VERSION 5.7 ;
  NOWIREEXTENSIONATPIN ON ;
  DIVIDERCHAR "/" ;
  BUSBITCHARS "[]" ;
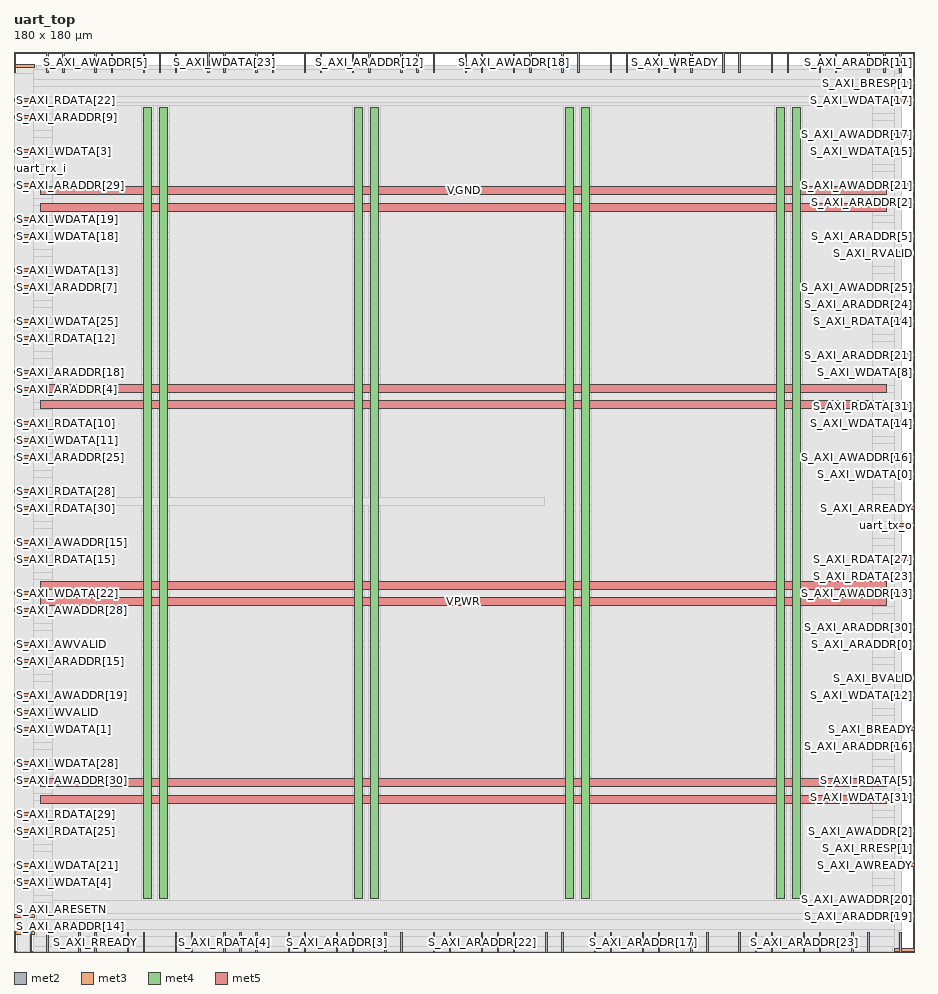
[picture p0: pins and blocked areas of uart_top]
MACRO uart_top
  CLASS BLOCK ;
  FOREIGN uart_top ;
  ORIGIN 0.000 0.000 ;
  SIZE 180.000 BY 180.000 ;
  PIN S_AXI_ACLK
    DIRECTION INPUT ;
    USE SIGNAL ;
    ANTENNAGATEAREA 0.213000 ;
    PORT
      LAYER met2 ;
        RECT 83.810 176.000 84.090 180.000 ;
    END
  END S_AXI_ACLK
  PIN S_AXI_ARADDR[0]
    DIRECTION INPUT ;
    USE SIGNAL ;
    ANTENNAGATEAREA 0.126000 ;
    PORT
      LAYER met3 ;
        RECT 176.000 61.240 180.000 61.840 ;
    END
  END S_AXI_ARADDR[0]
  PIN S_AXI_ARADDR[10]
    DIRECTION INPUT ;
    USE SIGNAL ;
    ANTENNAGATEAREA 0.196500 ;
    PORT
      LAYER met2 ;
        RECT 77.370 176.000 77.650 180.000 ;
    END
  END S_AXI_ARADDR[10]
  PIN S_AXI_ARADDR[11]
    DIRECTION INPUT ;
    USE SIGNAL ;
    ANTENNAGATEAREA 0.196500 ;
    PORT
      LAYER met2 ;
        RECT 170.750 176.000 171.030 180.000 ;
    END
  END S_AXI_ARADDR[11]
  PIN S_AXI_ARADDR[12]
    DIRECTION INPUT ;
    USE SIGNAL ;
    ANTENNAGATEAREA 0.196500 ;
    PORT
      LAYER met2 ;
        RECT 70.930 176.000 71.210 180.000 ;
    END
  END S_AXI_ARADDR[12]
  PIN S_AXI_ARADDR[13]
    DIRECTION INPUT ;
    USE SIGNAL ;
    ANTENNAGATEAREA 0.196500 ;
    PORT
      LAYER met2 ;
        RECT 122.450 176.000 122.730 180.000 ;
    END
  END S_AXI_ARADDR[13]
  PIN S_AXI_ARADDR[14]
    DIRECTION INPUT ;
    USE SIGNAL ;
    ANTENNAGATEAREA 0.126000 ;
    PORT
      LAYER met3 ;
        RECT 0.000 3.440 4.000 4.040 ;
    END
  END S_AXI_ARADDR[14]
  PIN S_AXI_ARADDR[15]
    DIRECTION INPUT ;
    USE SIGNAL ;
    ANTENNAGATEAREA 0.196500 ;
    PORT
      LAYER met3 ;
        RECT 0.000 57.840 4.000 58.440 ;
    END
  END S_AXI_ARADDR[15]
  PIN S_AXI_ARADDR[16]
    DIRECTION INPUT ;
    USE SIGNAL ;
    ANTENNAGATEAREA 0.196500 ;
    PORT
      LAYER met3 ;
        RECT 176.000 40.840 180.000 41.440 ;
    END
  END S_AXI_ARADDR[16]
  PIN S_AXI_ARADDR[17]
    DIRECTION INPUT ;
    USE SIGNAL ;
    ANTENNAGATEAREA 0.196500 ;
    PORT
      LAYER met2 ;
        RECT 125.670 0.000 125.950 4.000 ;
    END
  END S_AXI_ARADDR[17]
  PIN S_AXI_ARADDR[18]
    DIRECTION INPUT ;
    USE SIGNAL ;
    ANTENNAGATEAREA 0.213000 ;
    PORT
      LAYER met3 ;
        RECT 0.000 115.640 4.000 116.240 ;
    END
  END S_AXI_ARADDR[18]
  PIN S_AXI_ARADDR[19]
    DIRECTION INPUT ;
    USE SIGNAL ;
    ANTENNAGATEAREA 0.196500 ;
    PORT
      LAYER met3 ;
        RECT 176.000 6.840 180.000 7.440 ;
    END
  END S_AXI_ARADDR[19]
  PIN S_AXI_ARADDR[1]
    DIRECTION INPUT ;
    USE SIGNAL ;
    ANTENNAGATEAREA 0.196500 ;
    PORT
      LAYER met3 ;
        RECT 0.000 176.840 4.000 177.440 ;
    END
  END S_AXI_ARADDR[1]
  PIN S_AXI_ARADDR[20]
    DIRECTION INPUT ;
    USE SIGNAL ;
    ANTENNAGATEAREA 0.196500 ;
    PORT
      LAYER met2 ;
        RECT 19.410 176.000 19.690 180.000 ;
    END
  END S_AXI_ARADDR[20]
  PIN S_AXI_ARADDR[21]
    DIRECTION INPUT ;
    USE SIGNAL ;
    ANTENNAGATEAREA 0.196500 ;
    PORT
      LAYER met3 ;
        RECT 176.000 119.040 180.000 119.640 ;
    END
  END S_AXI_ARADDR[21]
  PIN S_AXI_ARADDR[22]
    DIRECTION INPUT ;
    USE SIGNAL ;
    ANTENNAGATEAREA 0.196500 ;
    PORT
      LAYER met2 ;
        RECT 93.470 0.000 93.750 4.000 ;
    END
  END S_AXI_ARADDR[22]
  PIN S_AXI_ARADDR[23]
    DIRECTION INPUT ;
    USE SIGNAL ;
    ANTENNAGATEAREA 0.196500 ;
    PORT
      LAYER met2 ;
        RECT 157.870 0.000 158.150 4.000 ;
    END
  END S_AXI_ARADDR[23]
  PIN S_AXI_ARADDR[24]
    DIRECTION INPUT ;
    USE SIGNAL ;
    ANTENNAGATEAREA 0.196500 ;
    PORT
      LAYER met3 ;
        RECT 176.000 129.240 180.000 129.840 ;
    END
  END S_AXI_ARADDR[24]
  PIN S_AXI_ARADDR[25]
    DIRECTION INPUT ;
    USE SIGNAL ;
    ANTENNAGATEAREA 0.196500 ;
    PORT
      LAYER met3 ;
        RECT 0.000 98.640 4.000 99.240 ;
    END
  END S_AXI_ARADDR[25]
  PIN S_AXI_ARADDR[26]
    DIRECTION INPUT ;
    USE SIGNAL ;
    ANTENNAGATEAREA 0.196500 ;
    PORT
      LAYER met2 ;
        RECT 9.750 176.000 10.030 180.000 ;
    END
  END S_AXI_ARADDR[26]
  PIN S_AXI_ARADDR[27]
    DIRECTION INPUT ;
    USE SIGNAL ;
    ANTENNAGATEAREA 0.196500 ;
    PORT
      LAYER met2 ;
        RECT 48.390 176.000 48.670 180.000 ;
    END
  END S_AXI_ARADDR[27]
  PIN S_AXI_ARADDR[28]
    DIRECTION INPUT ;
    USE SIGNAL ;
    ANTENNAGATEAREA 0.196500 ;
    PORT
      LAYER met2 ;
        RECT 25.850 0.000 26.130 4.000 ;
    END
  END S_AXI_ARADDR[28]
  PIN S_AXI_ARADDR[29]
    DIRECTION INPUT ;
    USE SIGNAL ;
    ANTENNAGATEAREA 0.126000 ;
    PORT
      LAYER met3 ;
        RECT 0.000 153.040 4.000 153.640 ;
    END
  END S_AXI_ARADDR[29]
  PIN S_AXI_ARADDR[2]
    DIRECTION INPUT ;
    USE SIGNAL ;
    ANTENNAGATEAREA 0.196500 ;
    PORT
      LAYER met3 ;
        RECT 176.000 149.640 180.000 150.240 ;
    END
  END S_AXI_ARADDR[2]
  PIN S_AXI_ARADDR[30]
    DIRECTION INPUT ;
    USE SIGNAL ;
    ANTENNAGATEAREA 0.196500 ;
    PORT
      LAYER met3 ;
        RECT 176.000 64.640 180.000 65.240 ;
    END
  END S_AXI_ARADDR[30]
  PIN S_AXI_ARADDR[31]
    DIRECTION INPUT ;
    USE SIGNAL ;
    ANTENNAGATEAREA 0.196500 ;
    PORT
      LAYER met2 ;
        RECT 128.890 0.000 129.170 4.000 ;
    END
  END S_AXI_ARADDR[31]
  PIN S_AXI_ARADDR[3]
    DIRECTION INPUT ;
    USE SIGNAL ;
    ANTENNAGATEAREA 0.213000 ;
    PORT
      LAYER met2 ;
        RECT 64.490 0.000 64.770 4.000 ;
    END
  END S_AXI_ARADDR[3]
  PIN S_AXI_ARADDR[4]
    DIRECTION INPUT ;
    USE SIGNAL ;
    ANTENNAGATEAREA 0.196500 ;
    PORT
      LAYER met3 ;
        RECT 0.000 112.240 4.000 112.840 ;
    END
  END S_AXI_ARADDR[4]
  PIN S_AXI_ARADDR[5]
    DIRECTION INPUT ;
    USE SIGNAL ;
    ANTENNAGATEAREA 0.196500 ;
    PORT
      LAYER met3 ;
        RECT 176.000 142.840 180.000 143.440 ;
    END
  END S_AXI_ARADDR[5]
  PIN S_AXI_ARADDR[6]
    DIRECTION INPUT ;
    USE SIGNAL ;
    ANTENNAGATEAREA 0.196500 ;
    PORT
      LAYER met2 ;
        RECT 112.790 176.000 113.070 180.000 ;
    END
  END S_AXI_ARADDR[6]
  PIN S_AXI_ARADDR[7]
    DIRECTION INPUT ;
    USE SIGNAL ;
    ANTENNAGATEAREA 0.196500 ;
    PORT
      LAYER met3 ;
        RECT 0.000 132.640 4.000 133.240 ;
    END
  END S_AXI_ARADDR[7]
  PIN S_AXI_ARADDR[8]
    DIRECTION INPUT ;
    USE SIGNAL ;
    ANTENNAGATEAREA 0.126000 ;
    PORT
      LAYER met2 ;
        RECT 45.170 0.000 45.450 4.000 ;
    END
  END S_AXI_ARADDR[8]
  PIN S_AXI_ARADDR[9]
    DIRECTION INPUT ;
    USE SIGNAL ;
    ANTENNAGATEAREA 0.196500 ;
    PORT
      LAYER met3 ;
        RECT 0.000 166.640 4.000 167.240 ;
    END
  END S_AXI_ARADDR[9]
  PIN S_AXI_ARESETN
    DIRECTION INPUT ;
    USE SIGNAL ;
    ANTENNAGATEAREA 0.213000 ;
    PORT
      LAYER met3 ;
        RECT 0.000 6.840 4.000 7.440 ;
    END
  END S_AXI_ARESETN
  PIN S_AXI_ARREADY
    DIRECTION OUTPUT TRISTATE ;
    USE SIGNAL ;
    ANTENNADIFFAREA 0.795200 ;
    PORT
      LAYER met3 ;
        RECT 176.000 88.440 180.000 89.040 ;
    END
  END S_AXI_ARREADY
  PIN S_AXI_ARVALID
    DIRECTION INPUT ;
    USE SIGNAL ;
    ANTENNAGATEAREA 0.196500 ;
    PORT
      LAYER met2 ;
        RECT 177.190 176.000 177.470 180.000 ;
    END
  END S_AXI_ARVALID
  PIN S_AXI_AWADDR[0]
    DIRECTION INPUT ;
    USE SIGNAL ;
    ANTENNAGATEAREA 0.196500 ;
    PORT
      LAYER met2 ;
        RECT 58.050 176.000 58.330 180.000 ;
    END
  END S_AXI_AWADDR[0]
  PIN S_AXI_AWADDR[10]
    DIRECTION INPUT ;
    USE SIGNAL ;
    ANTENNAGATEAREA 0.196500 ;
    PORT
      LAYER met2 ;
        RECT 12.970 0.000 13.250 4.000 ;
    END
  END S_AXI_AWADDR[10]
  PIN S_AXI_AWADDR[11]
    DIRECTION INPUT ;
    USE SIGNAL ;
    ANTENNAGATEAREA 0.196500 ;
    PORT
      LAYER met2 ;
        RECT 54.830 0.000 55.110 4.000 ;
    END
  END S_AXI_AWADDR[11]
  PIN S_AXI_AWADDR[12]
    DIRECTION INPUT ;
    USE SIGNAL ;
    ANTENNAGATEAREA 0.196500 ;
    PORT
      LAYER met2 ;
        RECT 167.530 0.000 167.810 4.000 ;
    END
  END S_AXI_AWADDR[12]
  PIN S_AXI_AWADDR[13]
    DIRECTION INPUT ;
    USE SIGNAL ;
    ANTENNAGATEAREA 0.196500 ;
    PORT
      LAYER met3 ;
        RECT 176.000 71.440 180.000 72.040 ;
    END
  END S_AXI_AWADDR[13]
  PIN S_AXI_AWADDR[14]
    DIRECTION INPUT ;
    USE SIGNAL ;
    ANTENNAGATEAREA 0.196500 ;
    PORT
      LAYER met2 ;
        RECT 116.010 0.000 116.290 4.000 ;
    END
  END S_AXI_AWADDR[14]
  PIN S_AXI_AWADDR[15]
    DIRECTION INPUT ;
    USE SIGNAL ;
    ANTENNAGATEAREA 0.196500 ;
    PORT
      LAYER met3 ;
        RECT 0.000 81.640 4.000 82.240 ;
    END
  END S_AXI_AWADDR[15]
  PIN S_AXI_AWADDR[16]
    DIRECTION INPUT ;
    USE SIGNAL ;
    ANTENNAGATEAREA 0.196500 ;
    PORT
      LAYER met3 ;
        RECT 176.000 98.640 180.000 99.240 ;
    END
  END S_AXI_AWADDR[16]
  PIN S_AXI_AWADDR[17]
    DIRECTION INPUT ;
    USE SIGNAL ;
    ANTENNAGATEAREA 0.196500 ;
    PORT
      LAYER met3 ;
        RECT 176.000 163.240 180.000 163.840 ;
    END
  END S_AXI_AWADDR[17]
  PIN S_AXI_AWADDR[18]
    DIRECTION INPUT ;
    USE SIGNAL ;
    ANTENNAGATEAREA 0.196500 ;
    PORT
      LAYER met2 ;
        RECT 99.910 176.000 100.190 180.000 ;
    END
  END S_AXI_AWADDR[18]
  PIN S_AXI_AWADDR[19]
    DIRECTION INPUT ;
    USE SIGNAL ;
    ANTENNAGATEAREA 0.126000 ;
    PORT
      LAYER met3 ;
        RECT 0.000 51.040 4.000 51.640 ;
    END
  END S_AXI_AWADDR[19]
  PIN S_AXI_AWADDR[1]
    DIRECTION INPUT ;
    USE SIGNAL ;
    ANTENNAGATEAREA 0.196500 ;
    PORT
      LAYER met2 ;
        RECT 80.590 176.000 80.870 180.000 ;
    END
  END S_AXI_AWADDR[1]
  PIN S_AXI_AWADDR[20]
    DIRECTION INPUT ;
    USE SIGNAL ;
    ANTENNAGATEAREA 0.196500 ;
    PORT
      LAYER met3 ;
        RECT 176.000 10.240 180.000 10.840 ;
    END
  END S_AXI_AWADDR[20]
  PIN S_AXI_AWADDR[21]
    DIRECTION INPUT ;
    USE SIGNAL ;
    ANTENNAGATEAREA 0.196500 ;
    PORT
      LAYER met3 ;
        RECT 176.000 153.040 180.000 153.640 ;
    END
  END S_AXI_AWADDR[21]
  PIN S_AXI_AWADDR[22]
    DIRECTION INPUT ;
    USE SIGNAL ;
    ANTENNAGATEAREA 0.196500 ;
    PORT
      LAYER met2 ;
        RECT 173.970 176.000 174.250 180.000 ;
    END
  END S_AXI_AWADDR[22]
  PIN S_AXI_AWADDR[23]
    DIRECTION INPUT ;
    USE SIGNAL ;
    ANTENNAGATEAREA 0.196500 ;
    PORT
      LAYER met2 ;
        RECT 61.270 176.000 61.550 180.000 ;
    END
  END S_AXI_AWADDR[23]
  PIN S_AXI_AWADDR[24]
    DIRECTION INPUT ;
    USE SIGNAL ;
    ANTENNAGATEAREA 0.196500 ;
    PORT
      LAYER met2 ;
        RECT 144.990 176.000 145.270 180.000 ;
    END
  END S_AXI_AWADDR[24]
  PIN S_AXI_AWADDR[25]
    DIRECTION INPUT ;
    USE SIGNAL ;
    ANTENNAGATEAREA 0.196500 ;
    PORT
      LAYER met3 ;
        RECT 176.000 132.640 180.000 133.240 ;
    END
  END S_AXI_AWADDR[25]
  PIN S_AXI_AWADDR[26]
    DIRECTION INPUT ;
    USE SIGNAL ;
    ANTENNAGATEAREA 0.196500 ;
    PORT
      LAYER met2 ;
        RECT 119.230 176.000 119.510 180.000 ;
    END
  END S_AXI_AWADDR[26]
  PIN S_AXI_AWADDR[27]
    DIRECTION INPUT ;
    USE SIGNAL ;
    ANTENNAGATEAREA 0.196500 ;
    PORT
      LAYER met2 ;
        RECT 135.330 0.000 135.610 4.000 ;
    END
  END S_AXI_AWADDR[27]
  PIN S_AXI_AWADDR[28]
    DIRECTION INPUT ;
    USE SIGNAL ;
    ANTENNAGATEAREA 0.196500 ;
    PORT
      LAYER met3 ;
        RECT 0.000 68.040 4.000 68.640 ;
    END
  END S_AXI_AWADDR[28]
  PIN S_AXI_AWADDR[29]
    DIRECTION INPUT ;
    USE SIGNAL ;
    ANTENNAGATEAREA 0.196500 ;
    PORT
      LAYER met2 ;
        RECT 83.810 0.000 84.090 4.000 ;
    END
  END S_AXI_AWADDR[29]
  PIN S_AXI_AWADDR[2]
    DIRECTION INPUT ;
    USE SIGNAL ;
    ANTENNAGATEAREA 0.213000 ;
    PORT
      LAYER met3 ;
        RECT 176.000 23.840 180.000 24.440 ;
    END
  END S_AXI_AWADDR[2]
  PIN S_AXI_AWADDR[30]
    DIRECTION INPUT ;
    USE SIGNAL ;
    ANTENNAGATEAREA 0.196500 ;
    PORT
      LAYER met3 ;
        RECT 0.000 34.040 4.000 34.640 ;
    END
  END S_AXI_AWADDR[30]
  PIN S_AXI_AWADDR[31]
    DIRECTION INPUT ;
    USE SIGNAL ;
    ANTENNAGATEAREA 0.126000 ;
    PORT
      LAYER met2 ;
        RECT 151.430 176.000 151.710 180.000 ;
    END
  END S_AXI_AWADDR[31]
  PIN S_AXI_AWADDR[3]
    DIRECTION INPUT ;
    USE SIGNAL ;
    ANTENNAGATEAREA 0.213000 ;
    PORT
      LAYER met2 ;
        RECT 74.150 0.000 74.430 4.000 ;
    END
  END S_AXI_AWADDR[3]
  PIN S_AXI_AWADDR[4]
    DIRECTION INPUT ;
    USE SIGNAL ;
    ANTENNAGATEAREA 0.126000 ;
    PORT
      LAYER met2 ;
        RECT 109.570 0.000 109.850 4.000 ;
    END
  END S_AXI_AWADDR[4]
  PIN S_AXI_AWADDR[5]
    DIRECTION INPUT ;
    USE SIGNAL ;
    ANTENNAGATEAREA 0.196500 ;
    PORT
      LAYER met2 ;
        RECT 16.190 176.000 16.470 180.000 ;
    END
  END S_AXI_AWADDR[5]
  PIN S_AXI_AWADDR[6]
    DIRECTION INPUT ;
    USE SIGNAL ;
    ANTENNAGATEAREA 0.126000 ;
    PORT
      LAYER met2 ;
        RECT 48.390 0.000 48.670 4.000 ;
    END
  END S_AXI_AWADDR[6]
  PIN S_AXI_AWADDR[7]
    DIRECTION INPUT ;
    USE SIGNAL ;
    ANTENNAGATEAREA 0.196500 ;
    PORT
      LAYER met2 ;
        RECT 6.530 176.000 6.810 180.000 ;
    END
  END S_AXI_AWADDR[7]
  PIN S_AXI_AWADDR[8]
    DIRECTION INPUT ;
    USE SIGNAL ;
    ANTENNAGATEAREA 0.196500 ;
    PORT
      LAYER met2 ;
        RECT 90.250 176.000 90.530 180.000 ;
    END
  END S_AXI_AWADDR[8]
  PIN S_AXI_AWADDR[9]
    DIRECTION INPUT ;
    USE SIGNAL ;
    ANTENNAGATEAREA 0.196500 ;
    PORT
      LAYER met2 ;
        RECT 151.430 0.000 151.710 4.000 ;
    END
  END S_AXI_AWADDR[9]
  PIN S_AXI_AWREADY
    DIRECTION OUTPUT TRISTATE ;
    USE SIGNAL ;
    ANTENNADIFFAREA 0.795200 ;
    PORT
      LAYER met3 ;
        RECT 176.000 17.040 180.000 17.640 ;
    END
  END S_AXI_AWREADY
  PIN S_AXI_AWVALID
    DIRECTION INPUT ;
    USE SIGNAL ;
    ANTENNAGATEAREA 0.196500 ;
    PORT
      LAYER met3 ;
        RECT 0.000 61.240 4.000 61.840 ;
    END
  END S_AXI_AWVALID
  PIN S_AXI_BREADY
    DIRECTION INPUT ;
    USE SIGNAL ;
    ANTENNAGATEAREA 0.196500 ;
    PORT
      LAYER met3 ;
        RECT 176.000 44.240 180.000 44.840 ;
    END
  END S_AXI_BREADY
  PIN S_AXI_BRESP[0]
    DIRECTION OUTPUT TRISTATE ;
    USE SIGNAL ;
    PORT
      LAYER met2 ;
        RECT 144.990 0.000 145.270 4.000 ;
    END
  END S_AXI_BRESP[0]
  PIN S_AXI_BRESP[1]
    DIRECTION OUTPUT TRISTATE ;
    USE SIGNAL ;
    PORT
      LAYER met3 ;
        RECT 176.000 173.440 180.000 174.040 ;
    END
  END S_AXI_BRESP[1]
  PIN S_AXI_BVALID
    DIRECTION OUTPUT TRISTATE ;
    USE SIGNAL ;
    ANTENNADIFFAREA 0.795200 ;
    PORT
      LAYER met3 ;
        RECT 176.000 54.440 180.000 55.040 ;
    END
  END S_AXI_BVALID
  PIN S_AXI_RDATA[0]
    DIRECTION OUTPUT TRISTATE ;
    USE SIGNAL ;
    ANTENNADIFFAREA 0.795200 ;
    PORT
      LAYER met2 ;
        RECT 77.370 0.000 77.650 4.000 ;
    END
  END S_AXI_RDATA[0]
  PIN S_AXI_RDATA[10]
    DIRECTION OUTPUT TRISTATE ;
    USE SIGNAL ;
    ANTENNADIFFAREA 0.795200 ;
    PORT
      LAYER met3 ;
        RECT 0.000 105.440 4.000 106.040 ;
    END
  END S_AXI_RDATA[10]
  PIN S_AXI_RDATA[11]
    DIRECTION OUTPUT TRISTATE ;
    USE SIGNAL ;
    ANTENNADIFFAREA 0.795200 ;
    PORT
      LAYER met2 ;
        RECT 135.330 176.000 135.610 180.000 ;
    END
  END S_AXI_RDATA[11]
  PIN S_AXI_RDATA[12]
    DIRECTION OUTPUT TRISTATE ;
    USE SIGNAL ;
    ANTENNADIFFAREA 0.795200 ;
    PORT
      LAYER met3 ;
        RECT 0.000 122.440 4.000 123.040 ;
    END
  END S_AXI_RDATA[12]
  PIN S_AXI_RDATA[13]
    DIRECTION OUTPUT TRISTATE ;
    USE SIGNAL ;
    ANTENNADIFFAREA 0.445500 ;
    PORT
      LAYER met2 ;
        RECT 38.730 176.000 39.010 180.000 ;
    END
  END S_AXI_RDATA[13]
  PIN S_AXI_RDATA[14]
    DIRECTION OUTPUT TRISTATE ;
    USE SIGNAL ;
    ANTENNADIFFAREA 0.795200 ;
    PORT
      LAYER met3 ;
        RECT 176.000 125.840 180.000 126.440 ;
    END
  END S_AXI_RDATA[14]
  PIN S_AXI_RDATA[15]
    DIRECTION OUTPUT TRISTATE ;
    USE SIGNAL ;
    ANTENNADIFFAREA 0.795200 ;
    PORT
      LAYER met3 ;
        RECT 0.000 78.240 4.000 78.840 ;
    END
  END S_AXI_RDATA[15]
  PIN S_AXI_RDATA[16]
    DIRECTION OUTPUT TRISTATE ;
    USE SIGNAL ;
    ANTENNADIFFAREA 0.445500 ;
    PORT
      LAYER met2 ;
        RECT 141.770 176.000 142.050 180.000 ;
    END
  END S_AXI_RDATA[16]
  PIN S_AXI_RDATA[17]
    DIRECTION OUTPUT TRISTATE ;
    USE SIGNAL ;
    ANTENNADIFFAREA 0.795200 ;
    PORT
      LAYER met2 ;
        RECT 109.570 176.000 109.850 180.000 ;
    END
  END S_AXI_RDATA[17]
  PIN S_AXI_RDATA[18]
    DIRECTION OUTPUT TRISTATE ;
    USE SIGNAL ;
    ANTENNADIFFAREA 0.445500 ;
    PORT
      LAYER met2 ;
        RECT 161.090 176.000 161.370 180.000 ;
    END
  END S_AXI_RDATA[18]
  PIN S_AXI_RDATA[19]
    DIRECTION OUTPUT TRISTATE ;
    USE SIGNAL ;
    ANTENNADIFFAREA 0.795200 ;
    PORT
      LAYER met2 ;
        RECT 3.310 0.000 3.590 4.000 ;
    END
  END S_AXI_RDATA[19]
  PIN S_AXI_RDATA[1]
    DIRECTION OUTPUT TRISTATE ;
    USE SIGNAL ;
    ANTENNADIFFAREA 0.795200 ;
    PORT
      LAYER met2 ;
        RECT 22.630 0.000 22.910 4.000 ;
    END
  END S_AXI_RDATA[1]
  PIN S_AXI_RDATA[20]
    DIRECTION OUTPUT TRISTATE ;
    USE SIGNAL ;
    ANTENNADIFFAREA 0.795200 ;
    PORT
      LAYER met3 ;
        RECT 176.000 0.040 180.000 0.640 ;
    END
  END S_AXI_RDATA[20]
  PIN S_AXI_RDATA[21]
    DIRECTION OUTPUT TRISTATE ;
    USE SIGNAL ;
    ANTENNADIFFAREA 0.795200 ;
    PORT
      LAYER met2 ;
        RECT 29.070 176.000 29.350 180.000 ;
    END
  END S_AXI_RDATA[21]
  PIN S_AXI_RDATA[22]
    DIRECTION OUTPUT TRISTATE ;
    USE SIGNAL ;
    ANTENNADIFFAREA 0.795200 ;
    PORT
      LAYER met3 ;
        RECT 0.000 170.040 4.000 170.640 ;
    END
  END S_AXI_RDATA[22]
  PIN S_AXI_RDATA[23]
    DIRECTION OUTPUT TRISTATE ;
    USE SIGNAL ;
    ANTENNADIFFAREA 0.795200 ;
    PORT
      LAYER met3 ;
        RECT 176.000 74.840 180.000 75.440 ;
    END
  END S_AXI_RDATA[23]
  PIN S_AXI_RDATA[24]
    DIRECTION OUTPUT TRISTATE ;
    USE SIGNAL ;
    ANTENNADIFFAREA 0.795200 ;
    PORT
      LAYER met2 ;
        RECT 67.710 176.000 67.990 180.000 ;
    END
  END S_AXI_RDATA[24]
  PIN S_AXI_RDATA[25]
    DIRECTION OUTPUT TRISTATE ;
    USE SIGNAL ;
    ANTENNADIFFAREA 0.795200 ;
    PORT
      LAYER met3 ;
        RECT 0.000 23.840 4.000 24.440 ;
    END
  END S_AXI_RDATA[25]
  PIN S_AXI_RDATA[26]
    DIRECTION OUTPUT TRISTATE ;
    USE SIGNAL ;
    ANTENNADIFFAREA 0.795200 ;
    PORT
      LAYER met2 ;
        RECT 25.850 176.000 26.130 180.000 ;
    END
  END S_AXI_RDATA[26]
  PIN S_AXI_RDATA[27]
    DIRECTION OUTPUT TRISTATE ;
    USE SIGNAL ;
    ANTENNADIFFAREA 0.795200 ;
    PORT
      LAYER met3 ;
        RECT 176.000 78.240 180.000 78.840 ;
    END
  END S_AXI_RDATA[27]
  PIN S_AXI_RDATA[28]
    DIRECTION OUTPUT TRISTATE ;
    USE SIGNAL ;
    ANTENNADIFFAREA 0.795200 ;
    PORT
      LAYER met3 ;
        RECT 0.000 91.840 4.000 92.440 ;
    END
  END S_AXI_RDATA[28]
  PIN S_AXI_RDATA[29]
    DIRECTION OUTPUT TRISTATE ;
    USE SIGNAL ;
    ANTENNADIFFAREA 0.795200 ;
    PORT
      LAYER met3 ;
        RECT 0.000 27.240 4.000 27.840 ;
    END
  END S_AXI_RDATA[29]
  PIN S_AXI_RDATA[2]
    DIRECTION OUTPUT TRISTATE ;
    USE SIGNAL ;
    ANTENNADIFFAREA 0.795200 ;
    PORT
      LAYER met2 ;
        RECT 170.750 0.000 171.030 4.000 ;
    END
  END S_AXI_RDATA[2]
  PIN S_AXI_RDATA[30]
    DIRECTION OUTPUT TRISTATE ;
    USE SIGNAL ;
    ANTENNADIFFAREA 0.795200 ;
    PORT
      LAYER met3 ;
        RECT 0.000 88.440 4.000 89.040 ;
    END
  END S_AXI_RDATA[30]
  PIN S_AXI_RDATA[31]
    DIRECTION OUTPUT TRISTATE ;
    USE SIGNAL ;
    ANTENNADIFFAREA 0.795200 ;
    PORT
      LAYER met3 ;
        RECT 176.000 108.840 180.000 109.440 ;
    END
  END S_AXI_RDATA[31]
  PIN S_AXI_RDATA[3]
    DIRECTION OUTPUT TRISTATE ;
    USE SIGNAL ;
    ANTENNADIFFAREA 0.795200 ;
    PORT
      LAYER met2 ;
        RECT 164.310 176.000 164.590 180.000 ;
    END
  END S_AXI_RDATA[3]
  PIN S_AXI_RDATA[4]
    DIRECTION OUTPUT TRISTATE ;
    USE SIGNAL ;
    ANTENNADIFFAREA 0.795200 ;
    PORT
      LAYER met2 ;
        RECT 41.950 0.000 42.230 4.000 ;
    END
  END S_AXI_RDATA[4]
  PIN S_AXI_RDATA[5]
    DIRECTION OUTPUT TRISTATE ;
    USE SIGNAL ;
    ANTENNADIFFAREA 0.795200 ;
    PORT
      LAYER met3 ;
        RECT 176.000 34.040 180.000 34.640 ;
    END
  END S_AXI_RDATA[5]
  PIN S_AXI_RDATA[6]
    DIRECTION OUTPUT TRISTATE ;
    USE SIGNAL ;
    ANTENNADIFFAREA 0.795200 ;
    PORT
      LAYER met2 ;
        RECT 106.350 0.000 106.630 4.000 ;
    END
  END S_AXI_RDATA[6]
  PIN S_AXI_RDATA[7]
    DIRECTION OUTPUT TRISTATE ;
    USE SIGNAL ;
    ANTENNADIFFAREA 0.795200 ;
    PORT
      LAYER met2 ;
        RECT 177.190 0.000 177.470 4.000 ;
    END
  END S_AXI_RDATA[7]
  PIN S_AXI_RDATA[8]
    DIRECTION OUTPUT TRISTATE ;
    USE SIGNAL ;
    ANTENNADIFFAREA 0.445500 ;
    PORT
      LAYER met2 ;
        RECT 51.610 176.000 51.890 180.000 ;
    END
  END S_AXI_RDATA[8]
  PIN S_AXI_RDATA[9]
    DIRECTION OUTPUT TRISTATE ;
    USE SIGNAL ;
    ANTENNADIFFAREA 0.795200 ;
    PORT
      LAYER met2 ;
        RECT 138.550 0.000 138.830 4.000 ;
    END
  END S_AXI_RDATA[9]
  PIN S_AXI_RREADY
    DIRECTION INPUT ;
    USE SIGNAL ;
    ANTENNAGATEAREA 0.213000 ;
    PORT
      LAYER met2 ;
        RECT 16.190 0.000 16.470 4.000 ;
    END
  END S_AXI_RREADY
  PIN S_AXI_RRESP[0]
    DIRECTION OUTPUT TRISTATE ;
    USE SIGNAL ;
    PORT
      LAYER met2 ;
        RECT 67.710 0.000 67.990 4.000 ;
    END
  END S_AXI_RRESP[0]
  PIN S_AXI_RRESP[1]
    DIRECTION OUTPUT TRISTATE ;
    USE SIGNAL ;
    PORT
      LAYER met3 ;
        RECT 176.000 20.440 180.000 21.040 ;
    END
  END S_AXI_RRESP[1]
  PIN S_AXI_RVALID
    DIRECTION OUTPUT TRISTATE ;
    USE SIGNAL ;
    ANTENNADIFFAREA 0.795200 ;
    PORT
      LAYER met3 ;
        RECT 176.000 139.440 180.000 140.040 ;
    END
  END S_AXI_RVALID
  PIN S_AXI_WDATA[0]
    DIRECTION INPUT ;
    USE SIGNAL ;
    ANTENNAGATEAREA 0.213000 ;
    PORT
      LAYER met3 ;
        RECT 176.000 95.240 180.000 95.840 ;
    END
  END S_AXI_WDATA[0]
  PIN S_AXI_WDATA[10]
    DIRECTION INPUT ;
    USE SIGNAL ;
    ANTENNAGATEAREA 0.213000 ;
    PORT
      LAYER met2 ;
        RECT 148.210 0.000 148.490 4.000 ;
    END
  END S_AXI_WDATA[10]
  PIN S_AXI_WDATA[11]
    DIRECTION INPUT ;
    USE SIGNAL ;
    ANTENNAGATEAREA 0.213000 ;
    PORT
      LAYER met3 ;
        RECT 0.000 102.040 4.000 102.640 ;
    END
  END S_AXI_WDATA[11]
  PIN S_AXI_WDATA[12]
    DIRECTION INPUT ;
    USE SIGNAL ;
    ANTENNAGATEAREA 0.213000 ;
    PORT
      LAYER met3 ;
        RECT 176.000 51.040 180.000 51.640 ;
    END
  END S_AXI_WDATA[12]
  PIN S_AXI_WDATA[13]
    DIRECTION INPUT ;
    USE SIGNAL ;
    ANTENNAGATEAREA 0.213000 ;
    PORT
      LAYER met3 ;
        RECT 0.000 136.040 4.000 136.640 ;
    END
  END S_AXI_WDATA[13]
  PIN S_AXI_WDATA[14]
    DIRECTION INPUT ;
    USE SIGNAL ;
    ANTENNAGATEAREA 0.213000 ;
    PORT
      LAYER met3 ;
        RECT 176.000 105.440 180.000 106.040 ;
    END
  END S_AXI_WDATA[14]
  PIN S_AXI_WDATA[15]
    DIRECTION INPUT ;
    USE SIGNAL ;
    ANTENNAGATEAREA 0.213000 ;
    PORT
      LAYER met3 ;
        RECT 176.000 159.840 180.000 160.440 ;
    END
  END S_AXI_WDATA[15]
  PIN S_AXI_WDATA[16]
    DIRECTION INPUT ;
    USE SIGNAL ;
    ANTENNAGATEAREA 0.159000 ;
    PORT
      LAYER met2 ;
        RECT 161.090 0.000 161.370 4.000 ;
    END
  END S_AXI_WDATA[16]
  PIN S_AXI_WDATA[17]
    DIRECTION INPUT ;
    USE SIGNAL ;
    ANTENNAGATEAREA 0.159000 ;
    PORT
      LAYER met3 ;
        RECT 176.000 170.040 180.000 170.640 ;
    END
  END S_AXI_WDATA[17]
  PIN S_AXI_WDATA[18]
    DIRECTION INPUT ;
    USE SIGNAL ;
    ANTENNAGATEAREA 0.196500 ;
    PORT
      LAYER met3 ;
        RECT 0.000 142.840 4.000 143.440 ;
    END
  END S_AXI_WDATA[18]
  PIN S_AXI_WDATA[19]
    DIRECTION INPUT ;
    USE SIGNAL ;
    ANTENNAGATEAREA 0.196500 ;
    PORT
      LAYER met3 ;
        RECT 0.000 146.240 4.000 146.840 ;
    END
  END S_AXI_WDATA[19]
  PIN S_AXI_WDATA[1]
    DIRECTION INPUT ;
    USE SIGNAL ;
    ANTENNAGATEAREA 0.213000 ;
    PORT
      LAYER met3 ;
        RECT 0.000 44.240 4.000 44.840 ;
    END
  END S_AXI_WDATA[1]
  PIN S_AXI_WDATA[20]
    DIRECTION INPUT ;
    USE SIGNAL ;
    ANTENNAGATEAREA 0.126000 ;
    PORT
      LAYER met2 ;
        RECT 0.090 0.000 0.370 4.000 ;
    END
  END S_AXI_WDATA[20]
  PIN S_AXI_WDATA[21]
    DIRECTION INPUT ;
    USE SIGNAL ;
    ANTENNAGATEAREA 0.126000 ;
    PORT
      LAYER met3 ;
        RECT 0.000 17.040 4.000 17.640 ;
    END
  END S_AXI_WDATA[21]
  PIN S_AXI_WDATA[22]
    DIRECTION INPUT ;
    USE SIGNAL ;
    ANTENNAGATEAREA 0.196500 ;
    PORT
      LAYER met3 ;
        RECT 0.000 71.440 4.000 72.040 ;
    END
  END S_AXI_WDATA[22]
  PIN S_AXI_WDATA[23]
    DIRECTION INPUT ;
    USE SIGNAL ;
    ANTENNAGATEAREA 0.126000 ;
    PORT
      LAYER met2 ;
        RECT 41.950 176.000 42.230 180.000 ;
    END
  END S_AXI_WDATA[23]
  PIN S_AXI_WDATA[24]
    DIRECTION INPUT ;
    USE SIGNAL ;
    ANTENNAGATEAREA 0.213000 ;
    PORT
      LAYER met2 ;
        RECT 103.130 176.000 103.410 180.000 ;
    END
  END S_AXI_WDATA[24]
  PIN S_AXI_WDATA[25]
    DIRECTION INPUT ;
    USE SIGNAL ;
    ANTENNAGATEAREA 0.196500 ;
    PORT
      LAYER met3 ;
        RECT 0.000 125.840 4.000 126.440 ;
    END
  END S_AXI_WDATA[25]
  PIN S_AXI_WDATA[26]
    DIRECTION INPUT ;
    USE SIGNAL ;
    ANTENNAGATEAREA 0.213000 ;
    PORT
      LAYER met2 ;
        RECT 32.290 0.000 32.570 4.000 ;
    END
  END S_AXI_WDATA[26]
  PIN S_AXI_WDATA[27]
    DIRECTION INPUT ;
    USE SIGNAL ;
    ANTENNAGATEAREA 0.213000 ;
    PORT
      LAYER met2 ;
        RECT 6.530 0.000 6.810 4.000 ;
    END
  END S_AXI_WDATA[27]
  PIN S_AXI_WDATA[28]
    DIRECTION INPUT ;
    USE SIGNAL ;
    ANTENNAGATEAREA 0.213000 ;
    PORT
      LAYER met3 ;
        RECT 0.000 37.440 4.000 38.040 ;
    END
  END S_AXI_WDATA[28]
  PIN S_AXI_WDATA[29]
    DIRECTION INPUT ;
    USE SIGNAL ;
    ANTENNAGATEAREA 0.213000 ;
    PORT
      LAYER met2 ;
        RECT 93.470 176.000 93.750 180.000 ;
    END
  END S_AXI_WDATA[29]
  PIN S_AXI_WDATA[2]
    DIRECTION INPUT ;
    USE SIGNAL ;
    ANTENNAGATEAREA 0.213000 ;
    PORT
      LAYER met2 ;
        RECT 87.030 0.000 87.310 4.000 ;
    END
  END S_AXI_WDATA[2]
  PIN S_AXI_WDATA[30]
    DIRECTION INPUT ;
    USE SIGNAL ;
    ANTENNAGATEAREA 0.213000 ;
    PORT
      LAYER met2 ;
        RECT 154.650 176.000 154.930 180.000 ;
    END
  END S_AXI_WDATA[30]
  PIN S_AXI_WDATA[31]
    DIRECTION INPUT ;
    USE SIGNAL ;
    ANTENNAGATEAREA 0.213000 ;
    PORT
      LAYER met3 ;
        RECT 176.000 30.640 180.000 31.240 ;
    END
  END S_AXI_WDATA[31]
  PIN S_AXI_WDATA[3]
    DIRECTION INPUT ;
    USE SIGNAL ;
    ANTENNAGATEAREA 0.213000 ;
    PORT
      LAYER met3 ;
        RECT 0.000 159.840 4.000 160.440 ;
    END
  END S_AXI_WDATA[3]
  PIN S_AXI_WDATA[4]
    DIRECTION INPUT ;
    USE SIGNAL ;
    ANTENNAGATEAREA 0.159000 ;
    PORT
      LAYER met3 ;
        RECT 0.000 13.640 4.000 14.240 ;
    END
  END S_AXI_WDATA[4]
  PIN S_AXI_WDATA[5]
    DIRECTION INPUT ;
    USE SIGNAL ;
    ANTENNAGATEAREA 0.159000 ;
    PORT
      LAYER met2 ;
        RECT 35.510 0.000 35.790 4.000 ;
    END
  END S_AXI_WDATA[5]
  PIN S_AXI_WDATA[6]
    DIRECTION INPUT ;
    USE SIGNAL ;
    ANTENNAGATEAREA 0.213000 ;
    PORT
      LAYER met2 ;
        RECT 58.050 0.000 58.330 4.000 ;
    END
  END S_AXI_WDATA[6]
  PIN S_AXI_WDATA[7]
    DIRECTION INPUT ;
    USE SIGNAL ;
    ANTENNAGATEAREA 0.213000 ;
    PORT
      LAYER met2 ;
        RECT 96.690 0.000 96.970 4.000 ;
    END
  END S_AXI_WDATA[7]
  PIN S_AXI_WDATA[8]
    DIRECTION INPUT ;
    USE SIGNAL ;
    ANTENNAGATEAREA 0.126000 ;
    PORT
      LAYER met3 ;
        RECT 176.000 115.640 180.000 116.240 ;
    END
  END S_AXI_WDATA[8]
  PIN S_AXI_WDATA[9]
    DIRECTION INPUT ;
    USE SIGNAL ;
    ANTENNAGATEAREA 0.213000 ;
    PORT
      LAYER met2 ;
        RECT 99.910 0.000 100.190 4.000 ;
    END
  END S_AXI_WDATA[9]
  PIN S_AXI_WREADY
    DIRECTION OUTPUT TRISTATE ;
    USE SIGNAL ;
    ANTENNADIFFAREA 0.795200 ;
    PORT
      LAYER met2 ;
        RECT 132.110 176.000 132.390 180.000 ;
    END
  END S_AXI_WREADY
  PIN S_AXI_WSTRB[0]
    DIRECTION INPUT ;
    USE SIGNAL ;
    ANTENNAGATEAREA 0.196500 ;
    PORT
      LAYER met2 ;
        RECT 128.890 176.000 129.170 180.000 ;
    END
  END S_AXI_WSTRB[0]
  PIN S_AXI_WSTRB[1]
    DIRECTION INPUT ;
    USE SIGNAL ;
    ANTENNAGATEAREA 0.196500 ;
    PORT
      LAYER met2 ;
        RECT 0.090 176.000 0.370 180.000 ;
    END
  END S_AXI_WSTRB[1]
  PIN S_AXI_WSTRB[2]
    DIRECTION INPUT ;
    USE SIGNAL ;
    ANTENNAGATEAREA 0.196500 ;
    PORT
      LAYER met2 ;
        RECT 32.290 176.000 32.570 180.000 ;
    END
  END S_AXI_WSTRB[2]
  PIN S_AXI_WSTRB[3]
    DIRECTION INPUT ;
    USE SIGNAL ;
    ANTENNAGATEAREA 0.196500 ;
    PORT
      LAYER met2 ;
        RECT 119.230 0.000 119.510 4.000 ;
    END
  END S_AXI_WSTRB[3]
  PIN S_AXI_WVALID
    DIRECTION INPUT ;
    USE SIGNAL ;
    ANTENNAGATEAREA 0.196500 ;
    PORT
      LAYER met3 ;
        RECT 0.000 47.640 4.000 48.240 ;
    END
  END S_AXI_WVALID
  PIN VGND
    DIRECTION INOUT ;
    USE GROUND ;
    PORT
      LAYER met4 ;
        RECT 29.120 10.640 30.720 168.880 ;
    END
    PORT
      LAYER met4 ;
        RECT 71.325 10.640 72.925 168.880 ;
    END
    PORT
      LAYER met4 ;
        RECT 113.530 10.640 115.130 168.880 ;
    END
    PORT
      LAYER met4 ;
        RECT 155.735 10.640 157.335 168.880 ;
    END
    PORT
      LAYER met5 ;
        RECT 5.280 33.100 174.580 34.700 ;
    END
    PORT
      LAYER met5 ;
        RECT 5.280 72.540 174.580 74.140 ;
    END
    PORT
      LAYER met5 ;
        RECT 5.280 111.980 174.580 113.580 ;
    END
    PORT
      LAYER met5 ;
        RECT 5.280 151.420 174.580 153.020 ;
    END
  END VGND
  PIN VPWR
    DIRECTION INOUT ;
    USE POWER ;
    PORT
      LAYER met4 ;
        RECT 25.820 10.640 27.420 168.880 ;
    END
    PORT
      LAYER met4 ;
        RECT 68.025 10.640 69.625 168.880 ;
    END
    PORT
      LAYER met4 ;
        RECT 110.230 10.640 111.830 168.880 ;
    END
    PORT
      LAYER met4 ;
        RECT 152.435 10.640 154.035 168.880 ;
    END
    PORT
      LAYER met5 ;
        RECT 5.280 29.800 174.580 31.400 ;
    END
    PORT
      LAYER met5 ;
        RECT 5.280 69.240 174.580 70.840 ;
    END
    PORT
      LAYER met5 ;
        RECT 5.280 108.680 174.580 110.280 ;
    END
    PORT
      LAYER met5 ;
        RECT 5.280 148.120 174.580 149.720 ;
    END
  END VPWR
  PIN uart_rx_i
    DIRECTION INPUT ;
    USE SIGNAL ;
    ANTENNAGATEAREA 0.213000 ;
    PORT
      LAYER met3 ;
        RECT 0.000 156.440 4.000 157.040 ;
    END
  END uart_rx_i
  PIN uart_tx_o
    DIRECTION OUTPUT TRISTATE ;
    USE SIGNAL ;
    ANTENNADIFFAREA 0.795200 ;
    PORT
      LAYER met3 ;
        RECT 176.000 85.040 180.000 85.640 ;
    END
  END uart_tx_o
  OBS
      LAYER li1 ;
        RECT 5.520 10.795 174.340 168.725 ;
      LAYER met1 ;
        RECT 0.070 5.820 177.490 170.980 ;
      LAYER met2 ;
        RECT 0.650 175.720 6.250 177.325 ;
        RECT 7.090 175.720 9.470 177.325 ;
        RECT 10.310 175.720 15.910 177.325 ;
        RECT 16.750 175.720 19.130 177.325 ;
        RECT 19.970 175.720 25.570 177.325 ;
        RECT 26.410 175.720 28.790 177.325 ;
        RECT 29.630 175.720 32.010 177.325 ;
        RECT 32.850 175.720 38.450 177.325 ;
        RECT 39.290 175.720 41.670 177.325 ;
        RECT 42.510 175.720 48.110 177.325 ;
        RECT 48.950 175.720 51.330 177.325 ;
        RECT 52.170 175.720 57.770 177.325 ;
        RECT 58.610 175.720 60.990 177.325 ;
        RECT 61.830 175.720 67.430 177.325 ;
        RECT 68.270 175.720 70.650 177.325 ;
        RECT 71.490 175.720 77.090 177.325 ;
        RECT 77.930 175.720 80.310 177.325 ;
        RECT 81.150 175.720 83.530 177.325 ;
        RECT 84.370 175.720 89.970 177.325 ;
        RECT 90.810 175.720 93.190 177.325 ;
        RECT 94.030 175.720 99.630 177.325 ;
        RECT 100.470 175.720 102.850 177.325 ;
        RECT 103.690 175.720 109.290 177.325 ;
        RECT 110.130 175.720 112.510 177.325 ;
        RECT 113.350 175.720 118.950 177.325 ;
        RECT 119.790 175.720 122.170 177.325 ;
        RECT 123.010 175.720 128.610 177.325 ;
        RECT 129.450 175.720 131.830 177.325 ;
        RECT 132.670 175.720 135.050 177.325 ;
        RECT 135.890 175.720 141.490 177.325 ;
        RECT 142.330 175.720 144.710 177.325 ;
        RECT 145.550 175.720 151.150 177.325 ;
        RECT 151.990 175.720 154.370 177.325 ;
        RECT 155.210 175.720 160.810 177.325 ;
        RECT 161.650 175.720 164.030 177.325 ;
        RECT 164.870 175.720 170.470 177.325 ;
        RECT 171.310 175.720 173.690 177.325 ;
        RECT 174.530 175.720 176.910 177.325 ;
        RECT 0.100 4.280 177.460 175.720 ;
        RECT 0.650 0.155 3.030 4.280 ;
        RECT 3.870 0.155 6.250 4.280 ;
        RECT 7.090 0.155 12.690 4.280 ;
        RECT 13.530 0.155 15.910 4.280 ;
        RECT 16.750 0.155 22.350 4.280 ;
        RECT 23.190 0.155 25.570 4.280 ;
        RECT 26.410 0.155 32.010 4.280 ;
        RECT 32.850 0.155 35.230 4.280 ;
        RECT 36.070 0.155 41.670 4.280 ;
        RECT 42.510 0.155 44.890 4.280 ;
        RECT 45.730 0.155 48.110 4.280 ;
        RECT 48.950 0.155 54.550 4.280 ;
        RECT 55.390 0.155 57.770 4.280 ;
        RECT 58.610 0.155 64.210 4.280 ;
        RECT 65.050 0.155 67.430 4.280 ;
        RECT 68.270 0.155 73.870 4.280 ;
        RECT 74.710 0.155 77.090 4.280 ;
        RECT 77.930 0.155 83.530 4.280 ;
        RECT 84.370 0.155 86.750 4.280 ;
        RECT 87.590 0.155 93.190 4.280 ;
        RECT 94.030 0.155 96.410 4.280 ;
        RECT 97.250 0.155 99.630 4.280 ;
        RECT 100.470 0.155 106.070 4.280 ;
        RECT 106.910 0.155 109.290 4.280 ;
        RECT 110.130 0.155 115.730 4.280 ;
        RECT 116.570 0.155 118.950 4.280 ;
        RECT 119.790 0.155 125.390 4.280 ;
        RECT 126.230 0.155 128.610 4.280 ;
        RECT 129.450 0.155 135.050 4.280 ;
        RECT 135.890 0.155 138.270 4.280 ;
        RECT 139.110 0.155 144.710 4.280 ;
        RECT 145.550 0.155 147.930 4.280 ;
        RECT 148.770 0.155 151.150 4.280 ;
        RECT 151.990 0.155 157.590 4.280 ;
        RECT 158.430 0.155 160.810 4.280 ;
        RECT 161.650 0.155 167.250 4.280 ;
        RECT 168.090 0.155 170.470 4.280 ;
        RECT 171.310 0.155 176.910 4.280 ;
      LAYER met3 ;
        RECT 4.400 176.440 176.000 177.305 ;
        RECT 3.990 174.440 176.000 176.440 ;
        RECT 3.990 173.040 175.600 174.440 ;
        RECT 3.990 171.040 176.000 173.040 ;
        RECT 4.400 169.640 175.600 171.040 ;
        RECT 3.990 167.640 176.000 169.640 ;
        RECT 4.400 166.240 176.000 167.640 ;
        RECT 3.990 164.240 176.000 166.240 ;
        RECT 3.990 162.840 175.600 164.240 ;
        RECT 3.990 160.840 176.000 162.840 ;
        RECT 4.400 159.440 175.600 160.840 ;
        RECT 3.990 157.440 176.000 159.440 ;
        RECT 4.400 156.040 176.000 157.440 ;
        RECT 3.990 154.040 176.000 156.040 ;
        RECT 4.400 152.640 175.600 154.040 ;
        RECT 3.990 150.640 176.000 152.640 ;
        RECT 3.990 149.240 175.600 150.640 ;
        RECT 3.990 147.240 176.000 149.240 ;
        RECT 4.400 145.840 176.000 147.240 ;
        RECT 3.990 143.840 176.000 145.840 ;
        RECT 4.400 142.440 175.600 143.840 ;
        RECT 3.990 140.440 176.000 142.440 ;
        RECT 3.990 139.040 175.600 140.440 ;
        RECT 3.990 137.040 176.000 139.040 ;
        RECT 4.400 135.640 176.000 137.040 ;
        RECT 3.990 133.640 176.000 135.640 ;
        RECT 4.400 132.240 175.600 133.640 ;
        RECT 3.990 130.240 176.000 132.240 ;
        RECT 3.990 128.840 175.600 130.240 ;
        RECT 3.990 126.840 176.000 128.840 ;
        RECT 4.400 125.440 175.600 126.840 ;
        RECT 3.990 123.440 176.000 125.440 ;
        RECT 4.400 122.040 176.000 123.440 ;
        RECT 3.990 120.040 176.000 122.040 ;
        RECT 3.990 118.640 175.600 120.040 ;
        RECT 3.990 116.640 176.000 118.640 ;
        RECT 4.400 115.240 175.600 116.640 ;
        RECT 3.990 113.240 176.000 115.240 ;
        RECT 4.400 111.840 176.000 113.240 ;
        RECT 3.990 109.840 176.000 111.840 ;
        RECT 3.990 108.440 175.600 109.840 ;
        RECT 3.990 106.440 176.000 108.440 ;
        RECT 4.400 105.040 175.600 106.440 ;
        RECT 3.990 103.040 176.000 105.040 ;
        RECT 4.400 101.640 176.000 103.040 ;
        RECT 3.990 99.640 176.000 101.640 ;
        RECT 4.400 98.240 175.600 99.640 ;
        RECT 3.990 96.240 176.000 98.240 ;
        RECT 3.990 94.840 175.600 96.240 ;
        RECT 3.990 92.840 176.000 94.840 ;
        RECT 4.400 91.440 176.000 92.840 ;
        RECT 3.990 89.440 176.000 91.440 ;
        RECT 4.400 88.040 175.600 89.440 ;
        RECT 3.990 86.040 176.000 88.040 ;
        RECT 3.990 84.640 175.600 86.040 ;
        RECT 3.990 82.640 176.000 84.640 ;
        RECT 4.400 81.240 176.000 82.640 ;
        RECT 3.990 79.240 176.000 81.240 ;
        RECT 4.400 77.840 175.600 79.240 ;
        RECT 3.990 75.840 176.000 77.840 ;
        RECT 3.990 74.440 175.600 75.840 ;
        RECT 3.990 72.440 176.000 74.440 ;
        RECT 4.400 71.040 175.600 72.440 ;
        RECT 3.990 69.040 176.000 71.040 ;
        RECT 4.400 67.640 176.000 69.040 ;
        RECT 3.990 65.640 176.000 67.640 ;
        RECT 3.990 64.240 175.600 65.640 ;
        RECT 3.990 62.240 176.000 64.240 ;
        RECT 4.400 60.840 175.600 62.240 ;
        RECT 3.990 58.840 176.000 60.840 ;
        RECT 4.400 57.440 176.000 58.840 ;
        RECT 3.990 55.440 176.000 57.440 ;
        RECT 3.990 54.040 175.600 55.440 ;
        RECT 3.990 52.040 176.000 54.040 ;
        RECT 4.400 50.640 175.600 52.040 ;
        RECT 3.990 48.640 176.000 50.640 ;
        RECT 4.400 47.240 176.000 48.640 ;
        RECT 3.990 45.240 176.000 47.240 ;
        RECT 4.400 43.840 175.600 45.240 ;
        RECT 3.990 41.840 176.000 43.840 ;
        RECT 3.990 40.440 175.600 41.840 ;
        RECT 3.990 38.440 176.000 40.440 ;
        RECT 4.400 37.040 176.000 38.440 ;
        RECT 3.990 35.040 176.000 37.040 ;
        RECT 4.400 33.640 175.600 35.040 ;
        RECT 3.990 31.640 176.000 33.640 ;
        RECT 3.990 30.240 175.600 31.640 ;
        RECT 3.990 28.240 176.000 30.240 ;
        RECT 4.400 26.840 176.000 28.240 ;
        RECT 3.990 24.840 176.000 26.840 ;
        RECT 4.400 23.440 175.600 24.840 ;
        RECT 3.990 21.440 176.000 23.440 ;
        RECT 3.990 20.040 175.600 21.440 ;
        RECT 3.990 18.040 176.000 20.040 ;
        RECT 4.400 16.640 175.600 18.040 ;
        RECT 3.990 14.640 176.000 16.640 ;
        RECT 4.400 13.240 176.000 14.640 ;
        RECT 3.990 11.240 176.000 13.240 ;
        RECT 3.990 9.840 175.600 11.240 ;
        RECT 3.990 7.840 176.000 9.840 ;
        RECT 4.400 6.440 175.600 7.840 ;
        RECT 3.990 4.440 176.000 6.440 ;
        RECT 4.400 3.040 176.000 4.440 ;
        RECT 3.990 1.040 176.000 3.040 ;
        RECT 3.990 0.175 175.600 1.040 ;
      LAYER met4 ;
        RECT 7.655 169.280 171.745 169.825 ;
        RECT 7.655 10.240 25.420 169.280 ;
        RECT 27.820 10.240 28.720 169.280 ;
        RECT 31.120 10.240 67.625 169.280 ;
        RECT 70.025 10.240 70.925 169.280 ;
        RECT 73.325 10.240 109.830 169.280 ;
        RECT 112.230 10.240 113.130 169.280 ;
        RECT 115.530 10.240 152.035 169.280 ;
        RECT 154.435 10.240 155.335 169.280 ;
        RECT 157.735 10.240 171.745 169.280 ;
        RECT 7.655 7.655 171.745 10.240 ;
      LAYER met5 ;
        RECT 8.860 89.300 106.140 90.900 ;
  END
END uart_top
END LIBRARY

